VERSION 5.7 ;
  NOWIREEXTENSIONATPIN ON ;
  DIVIDERCHAR "/" ;
  BUSBITCHARS "[]" ;
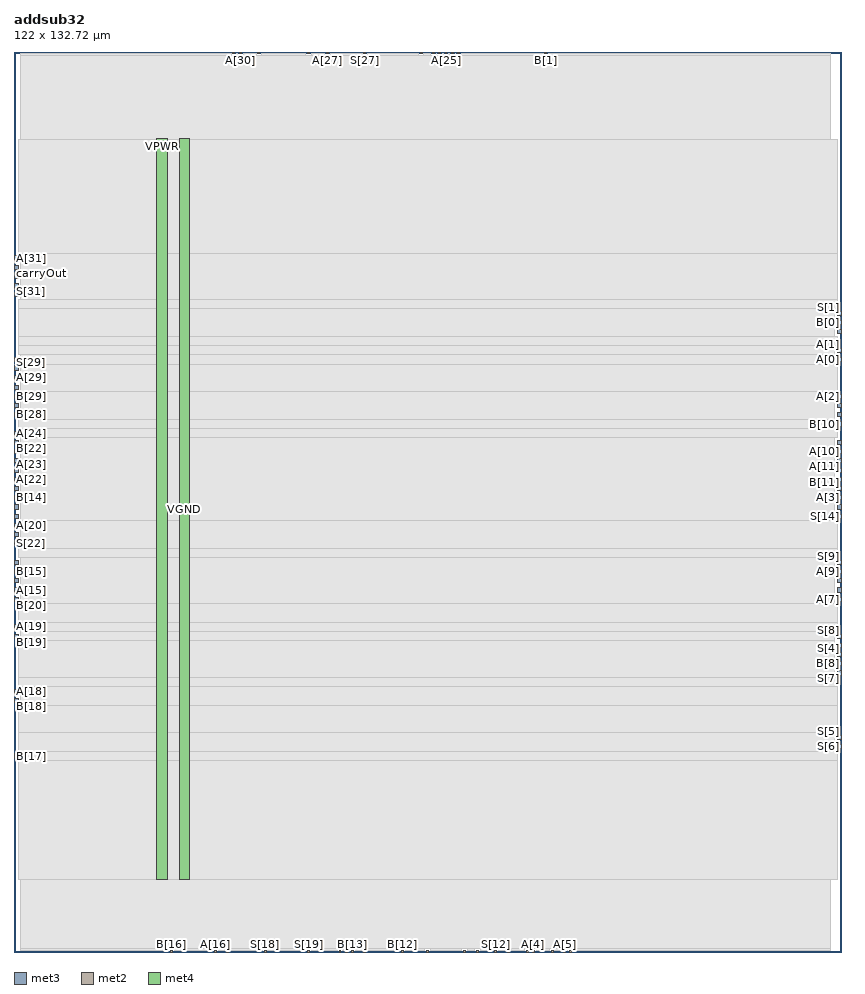
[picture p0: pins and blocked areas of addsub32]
MACRO addsub32
  CLASS BLOCK ;
  FOREIGN addsub32 ;
  ORIGIN 0.000 0.000 ;
  SIZE 122.000 BY 132.720 ;
  PIN A[0]
    DIRECTION INPUT ;
    USE SIGNAL ;
    ANTENNAGATEAREA 0.213000 ;
    PORT
      LAYER met3 ;
        RECT 121.400 87.080 122.000 87.680 ;
    END
  END A[0]
  PIN A[10]
    DIRECTION INPUT ;
    USE SIGNAL ;
    ANTENNAGATEAREA 0.213000 ;
    PORT
      LAYER met3 ;
        RECT 121.400 73.480 122.000 74.080 ;
    END
  END A[10]
  PIN A[11]
    DIRECTION INPUT ;
    USE SIGNAL ;
    ANTENNAGATEAREA 0.213000 ;
    PORT
      LAYER met3 ;
        RECT 121.400 72.120 122.000 72.720 ;
    END
  END A[11]
  PIN A[12]
    DIRECTION INPUT ;
    USE SIGNAL ;
    ANTENNAGATEAREA 0.213000 ;
    PORT
      LAYER met2 ;
        RECT 60.810 0.000 61.090 0.280 ;
    END
  END A[12]
  PIN A[13]
    DIRECTION INPUT ;
    USE SIGNAL ;
    ANTENNAGATEAREA 0.213000 ;
    PORT
      LAYER met2 ;
        RECT 51.610 0.000 51.890 0.280 ;
    END
  END A[13]
  PIN A[14]
    DIRECTION INPUT ;
    USE SIGNAL ;
    ANTENNAGATEAREA 0.213000 ;
    PORT
      LAYER met3 ;
        RECT 0.000 65.320 0.600 65.920 ;
    END
  END A[14]
  PIN A[15]
    DIRECTION INPUT ;
    USE SIGNAL ;
    ANTENNAGATEAREA 0.213000 ;
    PORT
      LAYER met3 ;
        RECT 0.000 53.080 0.600 53.680 ;
    END
  END A[15]
  PIN A[16]
    DIRECTION INPUT ;
    USE SIGNAL ;
    ANTENNAGATEAREA 0.213000 ;
    PORT
      LAYER met2 ;
        RECT 29.530 0.000 29.810 0.280 ;
    END
  END A[16]
  PIN A[17]
    DIRECTION INPUT ;
    USE SIGNAL ;
    ANTENNAGATEAREA 0.213000 ;
    PORT
      LAYER met2 ;
        RECT 31.370 0.000 31.650 0.280 ;
    END
  END A[17]
  PIN A[18]
    DIRECTION INPUT ;
    USE SIGNAL ;
    ANTENNAGATEAREA 0.213000 ;
    PORT
      LAYER met3 ;
        RECT 0.000 38.120 0.600 38.720 ;
    END
  END A[18]
  PIN A[19]
    DIRECTION INPUT ;
    USE SIGNAL ;
    ANTENNAGATEAREA 0.213000 ;
    PORT
      LAYER met3 ;
        RECT 0.000 47.640 0.600 48.240 ;
    END
  END A[19]
  PIN A[1]
    DIRECTION INPUT ;
    USE SIGNAL ;
    ANTENNAGATEAREA 0.213000 ;
    PORT
      LAYER met3 ;
        RECT 121.400 88.440 122.000 89.040 ;
    END
  END A[1]
  PIN A[20]
    DIRECTION INPUT ;
    USE SIGNAL ;
    ANTENNAGATEAREA 0.213000 ;
    PORT
      LAYER met3 ;
        RECT 0.000 62.600 0.600 63.200 ;
    END
  END A[20]
  PIN A[21]
    DIRECTION INPUT ;
    USE SIGNAL ;
    ANTENNAGATEAREA 0.213000 ;
    PORT
      LAYER met3 ;
        RECT 0.000 63.960 0.600 64.560 ;
    END
  END A[21]
  PIN A[22]
    DIRECTION INPUT ;
    USE SIGNAL ;
    ANTENNAGATEAREA 0.213000 ;
    PORT
      LAYER met3 ;
        RECT 0.000 69.400 0.600 70.000 ;
    END
  END A[22]
  PIN A[23]
    DIRECTION INPUT ;
    USE SIGNAL ;
    ANTENNAGATEAREA 0.213000 ;
    PORT
      LAYER met3 ;
        RECT 0.000 70.760 0.600 71.360 ;
    END
  END A[23]
  PIN A[24]
    DIRECTION INPUT ;
    USE SIGNAL ;
    ANTENNAGATEAREA 0.213000 ;
    PORT
      LAYER met3 ;
        RECT 0.000 76.200 0.600 76.800 ;
    END
  END A[24]
  PIN A[25]
    DIRECTION INPUT ;
    USE SIGNAL ;
    ANTENNAGATEAREA 0.213000 ;
    PORT
      LAYER met2 ;
        RECT 63.570 132.440 63.850 132.720 ;
    END
  END A[25]
  PIN A[26]
    DIRECTION INPUT ;
    USE SIGNAL ;
    ANTENNAGATEAREA 0.213000 ;
    PORT
      LAYER met2 ;
        RECT 62.650 132.440 62.930 132.720 ;
    END
  END A[26]
  PIN A[27]
    DIRECTION INPUT ;
    USE SIGNAL ;
    ANTENNAGATEAREA 0.213000 ;
    PORT
      LAYER met2 ;
        RECT 46.090 132.440 46.370 132.720 ;
    END
  END A[27]
  PIN A[28]
    DIRECTION INPUT ;
    USE SIGNAL ;
    ANTENNAGATEAREA 0.213000 ;
    PORT
      LAYER met3 ;
        RECT 0.000 87.080 0.600 87.680 ;
    END
  END A[28]
  PIN A[29]
    DIRECTION INPUT ;
    USE SIGNAL ;
    ANTENNAGATEAREA 0.213000 ;
    PORT
      LAYER met3 ;
        RECT 0.000 84.360 0.600 84.960 ;
    END
  END A[29]
  PIN A[2]
    DIRECTION INPUT ;
    USE SIGNAL ;
    ANTENNAGATEAREA 0.213000 ;
    PORT
      LAYER met3 ;
        RECT 121.400 81.640 122.000 82.240 ;
    END
  END A[2]
  PIN A[30]
    DIRECTION INPUT ;
    USE SIGNAL ;
    ANTENNAGATEAREA 0.213000 ;
    PORT
      LAYER met2 ;
        RECT 33.210 132.440 33.490 132.720 ;
    END
  END A[30]
  PIN A[31]
    DIRECTION INPUT ;
    USE SIGNAL ;
    ANTENNAGATEAREA 0.213000 ;
    PORT
      LAYER met3 ;
        RECT 0.000 102.040 0.600 102.640 ;
    END
  END A[31]
  PIN A[3]
    DIRECTION INPUT ;
    USE SIGNAL ;
    ANTENNAGATEAREA 0.213000 ;
    PORT
      LAYER met3 ;
        RECT 121.400 66.680 122.000 67.280 ;
    END
  END A[3]
  PIN A[4]
    DIRECTION INPUT ;
    USE SIGNAL ;
    ANTENNAGATEAREA 0.213000 ;
    PORT
      LAYER met2 ;
        RECT 76.450 0.000 76.730 0.280 ;
    END
  END A[4]
  PIN A[5]
    DIRECTION INPUT ;
    USE SIGNAL ;
    ANTENNAGATEAREA 0.213000 ;
    PORT
      LAYER met2 ;
        RECT 81.050 0.000 81.330 0.280 ;
    END
  END A[5]
  PIN A[6]
    DIRECTION INPUT ;
    USE SIGNAL ;
    ANTENNAGATEAREA 0.213000 ;
    PORT
      LAYER met2 ;
        RECT 81.970 0.000 82.250 0.280 ;
    END
  END A[6]
  PIN A[7]
    DIRECTION INPUT ;
    USE SIGNAL ;
    ANTENNAGATEAREA 0.213000 ;
    PORT
      LAYER met3 ;
        RECT 121.400 51.720 122.000 52.320 ;
    END
  END A[7]
  PIN A[8]
    DIRECTION INPUT ;
    USE SIGNAL ;
    ANTENNAGATEAREA 0.213000 ;
    PORT
      LAYER met3 ;
        RECT 121.400 44.920 122.000 45.520 ;
    END
  END A[8]
  PIN A[9]
    DIRECTION INPUT ;
    USE SIGNAL ;
    ANTENNAGATEAREA 0.213000 ;
    PORT
      LAYER met3 ;
        RECT 121.400 55.800 122.000 56.400 ;
    END
  END A[9]
  PIN B[0]
    DIRECTION INPUT ;
    USE SIGNAL ;
    ANTENNAGATEAREA 0.126000 ;
    PORT
      LAYER met3 ;
        RECT 121.400 92.520 122.000 93.120 ;
    END
  END B[0]
  PIN B[10]
    DIRECTION INPUT ;
    USE SIGNAL ;
    ANTENNAGATEAREA 0.213000 ;
    PORT
      LAYER met3 ;
        RECT 121.400 77.560 122.000 78.160 ;
    END
  END B[10]
  PIN B[11]
    DIRECTION INPUT ;
    USE SIGNAL ;
    ANTENNAGATEAREA 0.213000 ;
    PORT
      LAYER met3 ;
        RECT 121.400 68.040 122.000 68.640 ;
    END
  END B[11]
  PIN B[12]
    DIRECTION INPUT ;
    USE SIGNAL ;
    ANTENNAGATEAREA 0.213000 ;
    PORT
      LAYER met2 ;
        RECT 57.130 0.000 57.410 0.280 ;
    END
  END B[12]
  PIN B[13]
    DIRECTION INPUT ;
    USE SIGNAL ;
    ANTENNAGATEAREA 0.213000 ;
    PORT
      LAYER met2 ;
        RECT 49.770 0.000 50.050 0.280 ;
    END
  END B[13]
  PIN B[14]
    DIRECTION INPUT ;
    USE SIGNAL ;
    ANTENNAGATEAREA 0.213000 ;
    PORT
      LAYER met3 ;
        RECT 0.000 66.680 0.600 67.280 ;
    END
  END B[14]
  PIN B[15]
    DIRECTION INPUT ;
    USE SIGNAL ;
    ANTENNAGATEAREA 0.213000 ;
    PORT
      LAYER met3 ;
        RECT 0.000 55.800 0.600 56.400 ;
    END
  END B[15]
  PIN B[16]
    DIRECTION INPUT ;
    USE SIGNAL ;
    ANTENNAGATEAREA 0.213000 ;
    PORT
      LAYER met2 ;
        RECT 23.090 0.000 23.370 0.280 ;
    END
  END B[16]
  PIN B[17]
    DIRECTION INPUT ;
    USE SIGNAL ;
    ANTENNAGATEAREA 0.213000 ;
    PORT
      LAYER met3 ;
        RECT 0.000 28.600 0.600 29.200 ;
    END
  END B[17]
  PIN B[18]
    DIRECTION INPUT ;
    USE SIGNAL ;
    ANTENNAGATEAREA 0.213000 ;
    PORT
      LAYER met3 ;
        RECT 0.000 36.760 0.600 37.360 ;
    END
  END B[18]
  PIN B[19]
    DIRECTION INPUT ;
    USE SIGNAL ;
    ANTENNAGATEAREA 0.213000 ;
    PORT
      LAYER met3 ;
        RECT 0.000 46.280 0.600 46.880 ;
    END
  END B[19]
  PIN B[1]
    DIRECTION INPUT ;
    USE SIGNAL ;
    ANTENNAGATEAREA 0.213000 ;
    PORT
      LAYER met2 ;
        RECT 78.290 132.440 78.570 132.720 ;
    END
  END B[1]
  PIN B[20]
    DIRECTION INPUT ;
    USE SIGNAL ;
    ANTENNAGATEAREA 0.213000 ;
    PORT
      LAYER met3 ;
        RECT 0.000 51.720 0.600 52.320 ;
    END
  END B[20]
  PIN B[21]
    DIRECTION INPUT ;
    USE SIGNAL ;
    ANTENNAGATEAREA 0.213000 ;
    PORT
      LAYER met3 ;
        RECT 0.000 68.040 0.600 68.640 ;
    END
  END B[21]
  PIN B[22]
    DIRECTION INPUT ;
    USE SIGNAL ;
    ANTENNAGATEAREA 0.213000 ;
    PORT
      LAYER met3 ;
        RECT 0.000 74.840 0.600 75.440 ;
    END
  END B[22]
  PIN B[23]
    DIRECTION INPUT ;
    USE SIGNAL ;
    ANTENNAGATEAREA 0.213000 ;
    PORT
      LAYER met3 ;
        RECT 0.000 72.120 0.600 72.720 ;
    END
  END B[23]
  PIN B[24]
    DIRECTION INPUT ;
    USE SIGNAL ;
    ANTENNAGATEAREA 0.213000 ;
    PORT
      LAYER met3 ;
        RECT 0.000 73.480 0.600 74.080 ;
    END
  END B[24]
  PIN B[25]
    DIRECTION INPUT ;
    USE SIGNAL ;
    ANTENNAGATEAREA 0.213000 ;
    PORT
      LAYER met2 ;
        RECT 65.410 132.440 65.690 132.720 ;
    END
  END B[25]
  PIN B[26]
    DIRECTION INPUT ;
    USE SIGNAL ;
    ANTENNAGATEAREA 0.213000 ;
    PORT
      LAYER met2 ;
        RECT 64.490 132.440 64.770 132.720 ;
    END
  END B[26]
  PIN B[27]
    DIRECTION INPUT ;
    USE SIGNAL ;
    ANTENNAGATEAREA 0.213000 ;
    PORT
      LAYER met2 ;
        RECT 43.330 132.440 43.610 132.720 ;
    END
  END B[27]
  PIN B[28]
    DIRECTION INPUT ;
    USE SIGNAL ;
    ANTENNAGATEAREA 0.213000 ;
    PORT
      LAYER met3 ;
        RECT 0.000 78.920 0.600 79.520 ;
    END
  END B[28]
  PIN B[29]
    DIRECTION INPUT ;
    USE SIGNAL ;
    ANTENNAGATEAREA 0.213000 ;
    PORT
      LAYER met3 ;
        RECT 0.000 81.640 0.600 82.240 ;
    END
  END B[29]
  PIN B[2]
    DIRECTION INPUT ;
    USE SIGNAL ;
    ANTENNAGATEAREA 0.213000 ;
    PORT
      LAYER met3 ;
        RECT 121.400 80.280 122.000 80.880 ;
    END
  END B[2]
  PIN B[30]
    DIRECTION INPUT ;
    USE SIGNAL ;
    ANTENNAGATEAREA 0.213000 ;
    PORT
      LAYER met2 ;
        RECT 32.290 132.440 32.570 132.720 ;
    END
  END B[30]
  PIN B[31]
    DIRECTION INPUT ;
    USE SIGNAL ;
    ANTENNAGATEAREA 0.213000 ;
    PORT
      LAYER met3 ;
        RECT 0.000 99.320 0.600 99.920 ;
    END
  END B[31]
  PIN B[3]
    DIRECTION INPUT ;
    USE SIGNAL ;
    ANTENNAGATEAREA 0.213000 ;
    PORT
      LAYER met3 ;
        RECT 121.400 65.320 122.000 65.920 ;
    END
  END B[3]
  PIN B[4]
    DIRECTION INPUT ;
    USE SIGNAL ;
    ANTENNAGATEAREA 0.213000 ;
    PORT
      LAYER met2 ;
        RECT 72.770 0.000 73.050 0.280 ;
    END
  END B[4]
  PIN B[5]
    DIRECTION INPUT ;
    USE SIGNAL ;
    ANTENNAGATEAREA 0.213000 ;
    PORT
      LAYER met2 ;
        RECT 79.210 0.000 79.490 0.280 ;
    END
  END B[5]
  PIN B[6]
    DIRECTION INPUT ;
    USE SIGNAL ;
    ANTENNAGATEAREA 0.213000 ;
    PORT
      LAYER met2 ;
        RECT 75.530 0.000 75.810 0.280 ;
    END
  END B[6]
  PIN B[7]
    DIRECTION INPUT ;
    USE SIGNAL ;
    ANTENNAGATEAREA 0.213000 ;
    PORT
      LAYER met3 ;
        RECT 121.400 53.080 122.000 53.680 ;
    END
  END B[7]
  PIN B[8]
    DIRECTION INPUT ;
    USE SIGNAL ;
    ANTENNAGATEAREA 0.213000 ;
    PORT
      LAYER met3 ;
        RECT 121.400 42.200 122.000 42.800 ;
    END
  END B[8]
  PIN B[9]
    DIRECTION INPUT ;
    USE SIGNAL ;
    ANTENNAGATEAREA 0.213000 ;
    PORT
      LAYER met3 ;
        RECT 121.400 54.440 122.000 55.040 ;
    END
  END B[9]
  PIN S[0]
    DIRECTION OUTPUT ;
    USE SIGNAL ;
    ANTENNADIFFAREA 0.702900 ;
    PORT
      LAYER met3 ;
        RECT 121.400 91.160 122.000 91.760 ;
    END
  END S[0]
  PIN S[10]
    DIRECTION OUTPUT ;
    USE SIGNAL ;
    ANTENNADIFFAREA 0.795200 ;
    PORT
      LAYER met3 ;
        RECT 121.400 69.400 122.000 70.000 ;
    END
  END S[10]
  PIN S[11]
    DIRECTION OUTPUT ;
    USE SIGNAL ;
    ANTENNADIFFAREA 1.336500 ;
    PORT
      LAYER met3 ;
        RECT 121.400 70.760 122.000 71.360 ;
    END
  END S[11]
  PIN S[12]
    DIRECTION OUTPUT ;
    USE SIGNAL ;
    ANTENNADIFFAREA 0.702900 ;
    PORT
      LAYER met2 ;
        RECT 70.930 0.000 71.210 0.280 ;
    END
  END S[12]
  PIN S[13]
    DIRECTION OUTPUT ;
    USE SIGNAL ;
    ANTENNAGATEAREA 0.126000 ;
    ANTENNADIFFAREA 0.429000 ;
    PORT
      LAYER met2 ;
        RECT 68.170 0.000 68.450 0.280 ;
    END
  END S[13]
  PIN S[14]
    DIRECTION OUTPUT ;
    USE SIGNAL ;
    ANTENNADIFFAREA 1.336500 ;
    PORT
      LAYER met3 ;
        RECT 121.400 63.960 122.000 64.560 ;
    END
  END S[14]
  PIN S[15]
    DIRECTION OUTPUT ;
    USE SIGNAL ;
    ANTENNADIFFAREA 1.336500 ;
    PORT
      LAYER met2 ;
        RECT 66.330 0.000 66.610 0.280 ;
    END
  END S[15]
  PIN S[16]
    DIRECTION OUTPUT ;
    USE SIGNAL ;
    ANTENNAGATEAREA 0.126000 ;
    ANTENNADIFFAREA 0.429000 ;
    PORT
      LAYER met2 ;
        RECT 47.930 0.000 48.210 0.280 ;
    END
  END S[16]
  PIN S[17]
    DIRECTION OUTPUT ;
    USE SIGNAL ;
    ANTENNADIFFAREA 0.383400 ;
    PORT
      LAYER met2 ;
        RECT 48.850 0.000 49.130 0.280 ;
    END
  END S[17]
  PIN S[18]
    DIRECTION OUTPUT ;
    USE SIGNAL ;
    ANTENNADIFFAREA 0.795200 ;
    PORT
      LAYER met2 ;
        RECT 36.890 0.000 37.170 0.280 ;
    END
  END S[18]
  PIN S[19]
    DIRECTION OUTPUT ;
    USE SIGNAL ;
    ANTENNADIFFAREA 0.445500 ;
    PORT
      LAYER met2 ;
        RECT 43.330 0.000 43.610 0.280 ;
    END
  END S[19]
  PIN S[1]
    DIRECTION OUTPUT ;
    USE SIGNAL ;
    ANTENNADIFFAREA 0.702900 ;
    PORT
      LAYER met3 ;
        RECT 121.400 93.880 122.000 94.480 ;
    END
  END S[1]
  PIN S[20]
    DIRECTION OUTPUT ;
    USE SIGNAL ;
    ANTENNADIFFAREA 0.383400 ;
    PORT
      LAYER met3 ;
        RECT 0.000 57.160 0.600 57.760 ;
    END
  END S[20]
  PIN S[21]
    DIRECTION OUTPUT ;
    USE SIGNAL ;
    ANTENNADIFFAREA 1.336500 ;
    PORT
      LAYER met3 ;
        RECT 0.000 54.440 0.600 55.040 ;
    END
  END S[21]
  PIN S[22]
    DIRECTION OUTPUT ;
    USE SIGNAL ;
    ANTENNADIFFAREA 1.336500 ;
    PORT
      LAYER met3 ;
        RECT 0.000 59.880 0.600 60.480 ;
    END
  END S[22]
  PIN S[23]
    DIRECTION OUTPUT ;
    USE SIGNAL ;
    ANTENNADIFFAREA 1.336500 ;
    PORT
      LAYER met3 ;
        RECT 0.000 61.240 0.600 61.840 ;
    END
  END S[23]
  PIN S[24]
    DIRECTION OUTPUT ;
    USE SIGNAL ;
    ANTENNADIFFAREA 0.795200 ;
    PORT
      LAYER met3 ;
        RECT 0.000 80.280 0.600 80.880 ;
    END
  END S[24]
  PIN S[25]
    DIRECTION OUTPUT ;
    USE SIGNAL ;
    ANTENNADIFFAREA 1.336500 ;
    PORT
      LAYER met2 ;
        RECT 59.890 132.440 60.170 132.720 ;
    END
  END S[25]
  PIN S[26]
    DIRECTION OUTPUT ;
    USE SIGNAL ;
    ANTENNADIFFAREA 1.336500 ;
    PORT
      LAYER met2 ;
        RECT 61.730 132.440 62.010 132.720 ;
    END
  END S[26]
  PIN S[27]
    DIRECTION OUTPUT ;
    USE SIGNAL ;
    ANTENNADIFFAREA 0.891000 ;
    PORT
      LAYER met2 ;
        RECT 51.610 132.440 51.890 132.720 ;
    END
  END S[27]
  PIN S[28]
    DIRECTION OUTPUT ;
    USE SIGNAL ;
    ANTENNADIFFAREA 0.891000 ;
    PORT
      LAYER met3 ;
        RECT 0.000 83.000 0.600 83.600 ;
    END
  END S[28]
  PIN S[29]
    DIRECTION OUTPUT ;
    USE SIGNAL ;
    ANTENNADIFFAREA 1.336500 ;
    PORT
      LAYER met3 ;
        RECT 0.000 85.720 0.600 86.320 ;
    END
  END S[29]
  PIN S[2]
    DIRECTION OUTPUT ;
    USE SIGNAL ;
    ANTENNADIFFAREA 0.702900 ;
    PORT
      LAYER met3 ;
        RECT 121.400 78.920 122.000 79.520 ;
    END
  END S[2]
  PIN S[30]
    DIRECTION OUTPUT ;
    USE SIGNAL ;
    ANTENNADIFFAREA 1.336500 ;
    PORT
      LAYER met2 ;
        RECT 35.970 132.440 36.250 132.720 ;
    END
  END S[30]
  PIN S[31]
    DIRECTION OUTPUT ;
    USE SIGNAL ;
    ANTENNADIFFAREA 1.336500 ;
    PORT
      LAYER met3 ;
        RECT 0.000 97.960 0.600 98.560 ;
    END
  END S[31]
  PIN S[3]
    DIRECTION OUTPUT ;
    USE SIGNAL ;
    ANTENNADIFFAREA 0.702900 ;
    PORT
      LAYER met3 ;
        RECT 121.400 74.840 122.000 75.440 ;
    END
  END S[3]
  PIN S[4]
    DIRECTION OUTPUT ;
    USE SIGNAL ;
    ANTENNADIFFAREA 0.702900 ;
    PORT
      LAYER met3 ;
        RECT 121.400 43.560 122.000 44.160 ;
    END
  END S[4]
  PIN S[5]
    DIRECTION OUTPUT ;
    USE SIGNAL ;
    ANTENNADIFFAREA 0.702900 ;
    PORT
      LAYER met3 ;
        RECT 121.400 31.320 122.000 31.920 ;
    END
  END S[5]
  PIN S[6]
    DIRECTION OUTPUT ;
    USE SIGNAL ;
    ANTENNADIFFAREA 0.702900 ;
    PORT
      LAYER met3 ;
        RECT 121.400 29.960 122.000 30.560 ;
    END
  END S[6]
  PIN S[7]
    DIRECTION OUTPUT ;
    USE SIGNAL ;
    ANTENNAGATEAREA 0.126000 ;
    ANTENNADIFFAREA 0.429000 ;
    PORT
      LAYER met3 ;
        RECT 121.400 40.840 122.000 41.440 ;
    END
  END S[7]
  PIN S[8]
    DIRECTION OUTPUT ;
    USE SIGNAL ;
    ANTENNADIFFAREA 0.702900 ;
    PORT
      LAYER met3 ;
        RECT 121.400 46.280 122.000 46.880 ;
    END
  END S[8]
  PIN S[9]
    DIRECTION OUTPUT ;
    USE SIGNAL ;
    ANTENNADIFFAREA 1.336500 ;
    PORT
      LAYER met3 ;
        RECT 121.400 57.160 122.000 57.760 ;
    END
  END S[9]
  PIN VGND
    DIRECTION INOUT ;
    USE GROUND ;
    PORT
      LAYER met4 ;
        RECT 24.340 10.640 25.940 119.920 ;
    END
  END VGND
  PIN VPWR
    DIRECTION INOUT ;
    USE POWER ;
    PORT
      LAYER met4 ;
        RECT 21.040 10.640 22.640 119.920 ;
    END
  END VPWR
  PIN carryOut
    DIRECTION OUTPUT ;
    USE SIGNAL ;
    ANTENNADIFFAREA 1.336500 ;
    PORT
      LAYER met3 ;
        RECT 0.000 100.680 0.600 101.280 ;
    END
  END carryOut
  PIN sub
    DIRECTION INPUT ;
    USE SIGNAL ;
    ANTENNAGATEAREA 0.742500 ;
    PORT
      LAYER met3 ;
        RECT 0.000 96.600 0.600 97.200 ;
    END
  END sub
  OBS
      LAYER nwell ;
        RECT 5.330 10.795 116.570 119.765 ;
      LAYER li1 ;
        RECT 5.520 10.795 116.380 119.765 ;
      LAYER met1 ;
        RECT 0.990 5.820 120.450 119.920 ;
      LAYER met2 ;
        RECT 1.010 132.160 32.010 132.440 ;
        RECT 32.850 132.160 32.930 132.440 ;
        RECT 33.770 132.160 35.690 132.440 ;
        RECT 36.530 132.160 43.050 132.440 ;
        RECT 43.890 132.160 45.810 132.440 ;
        RECT 46.650 132.160 51.330 132.440 ;
        RECT 52.170 132.160 59.610 132.440 ;
        RECT 60.450 132.160 61.450 132.440 ;
        RECT 62.290 132.160 62.370 132.440 ;
        RECT 63.210 132.160 63.290 132.440 ;
        RECT 64.130 132.160 64.210 132.440 ;
        RECT 65.050 132.160 65.130 132.440 ;
        RECT 65.970 132.160 78.010 132.440 ;
        RECT 78.850 132.160 120.430 132.440 ;
        RECT 1.010 0.560 120.430 132.160 ;
        RECT 1.010 0.280 22.810 0.560 ;
        RECT 23.650 0.280 29.250 0.560 ;
        RECT 30.090 0.280 31.090 0.560 ;
        RECT 31.930 0.280 36.610 0.560 ;
        RECT 37.450 0.280 43.050 0.560 ;
        RECT 43.890 0.280 47.650 0.560 ;
        RECT 48.490 0.280 48.570 0.560 ;
        RECT 49.410 0.280 49.490 0.560 ;
        RECT 50.330 0.280 51.330 0.560 ;
        RECT 52.170 0.280 56.850 0.560 ;
        RECT 57.690 0.280 60.530 0.560 ;
        RECT 61.370 0.280 66.050 0.560 ;
        RECT 66.890 0.280 67.890 0.560 ;
        RECT 68.730 0.280 70.650 0.560 ;
        RECT 71.490 0.280 72.490 0.560 ;
        RECT 73.330 0.280 75.250 0.560 ;
        RECT 76.090 0.280 76.170 0.560 ;
        RECT 77.010 0.280 78.930 0.560 ;
        RECT 79.770 0.280 80.770 0.560 ;
        RECT 81.610 0.280 81.690 0.560 ;
        RECT 82.530 0.280 120.430 0.560 ;
      LAYER met3 ;
        RECT 0.600 103.040 121.400 119.845 ;
        RECT 1.000 96.200 121.400 103.040 ;
        RECT 0.600 94.880 121.400 96.200 ;
        RECT 0.600 90.760 121.000 94.880 ;
        RECT 0.600 89.440 121.400 90.760 ;
        RECT 0.600 88.080 121.000 89.440 ;
        RECT 1.000 86.680 121.000 88.080 ;
        RECT 1.000 82.640 121.400 86.680 ;
        RECT 1.000 78.520 121.000 82.640 ;
        RECT 0.600 77.200 121.000 78.520 ;
        RECT 1.000 77.160 121.000 77.200 ;
        RECT 1.000 75.840 121.400 77.160 ;
        RECT 1.000 63.560 121.000 75.840 ;
        RECT 1.000 59.480 121.400 63.560 ;
        RECT 0.600 58.160 121.400 59.480 ;
        RECT 1.000 51.320 121.000 58.160 ;
        RECT 0.600 48.640 121.400 51.320 ;
        RECT 1.000 47.280 121.400 48.640 ;
        RECT 1.000 45.880 121.000 47.280 ;
        RECT 0.600 40.440 121.000 45.880 ;
        RECT 0.600 39.120 121.400 40.440 ;
        RECT 1.000 36.360 121.400 39.120 ;
        RECT 0.600 32.320 121.400 36.360 ;
        RECT 0.600 29.600 121.000 32.320 ;
        RECT 1.000 29.560 121.000 29.600 ;
        RECT 1.000 28.200 121.400 29.560 ;
        RECT 0.600 10.715 121.400 28.200 ;
  END
END addsub32
END LIBRARY

